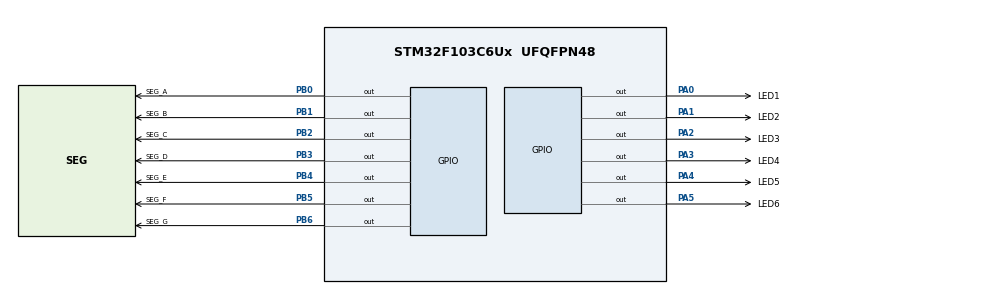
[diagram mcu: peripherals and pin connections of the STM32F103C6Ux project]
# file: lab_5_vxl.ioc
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Mcu.Family=STM32F1
Mcu.Name=STM32F103C6Ux
Mcu.Package=UFQFPN48
NVIC.PriorityGroup=NVIC_PRIORITYGROUP_4
PA0-WKUP.GPIO_Label=LED1
PA0-WKUP.Signal=GPIO_Output
PA1.GPIO_Label=LED2
PA1.Signal=GPIO_Output
PA2.GPIO_Label=LED3
PA2.Signal=GPIO_Output
PA3.GPIO_Label=LED4
PA3.Signal=GPIO_Output
PA4.GPIO_Label=LED5
PA4.Signal=GPIO_Output
PA5.GPIO_Label=LED6
PA5.Signal=GPIO_Output
PB0.GPIO_Label=SEG_A
PB0.Signal=GPIO_Output
PB1.GPIO_Label=SEG_B
PB1.Signal=GPIO_Output
PB2.GPIO_Label=SEG_C
PB2.Signal=GPIO_Output
PB3.GPIO_Label=SEG_D
PB3.Signal=GPIO_Output
PB4.GPIO_Label=SEG_E
PB4.Signal=GPIO_Output
PB5.GPIO_Label=SEG_F
PB5.Signal=GPIO_Output
PB6.GPIO_Label=SEG_G
PB6.Signal=GPIO_Output
ProjectManager.HeapSize=0x200
ProjectManager.StackSize=0x400
ProjectManager.TargetToolchain=STM32CubeIDE
RCC.APB1Freq_Value=8000000
RCC.APB2Freq_Value=8000000
VP_SYS_VS_ND.Mode=No_Debug
board=custom

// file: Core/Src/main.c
/* USER CODE BEGIN Header */
/**
  ******************************************************************************
  * @file           : main.c
  * @brief          : Main program body
  ******************************************************************************
  */

/* USER CODE END Header */

#include "main.h"

/* USER CODE BEGIN PD */

#define SCAN_COUNT      250
#define SCAN_DELAY_MS   2

/* Mau den */
#define RED      0
#define YELLOW   1
#define GREEN    2

/* USER CODE END PD */

void SystemClock_Config(void);
static void MX_GPIO_Init(void);

/* USER CODE BEGIN PFP */

void display7SEG(int num, uint32_t GPIO_Pin);

void allLEDOff(void);

void showTraffic(
    uint8_t verticalColor,
    uint8_t horizontalColor,
    GPIO_PinState phase
);

void runTrafficSecond(
    int verticalDisplay,
    int horizontalDisplay,
    uint8_t verticalColor,
    uint8_t horizontalColor
);

/* USER CODE END PFP */

/* USER CODE BEGIN 0 */

void display7SEG(int num, uint32_t GPIO_Pin)
{
    char segNumber[10] =
    {
        0xC0,
        0xF9,
        0xA4,
        0xB0,
        0x99,
        0x92,
        0x82,
        0xF8,
        0x80,
        0x90
    };

    for (int i = 0; i < 7; ++i)
    {
        HAL_GPIO_WritePin(
            GPIOB,
            GPIO_Pin << i,
            (segNumber[num] >> i) & 1
        );
    }
}

void allLEDOff(void)
{
    HAL_GPIO_WritePin(
        GPIOA,
        GPIO_PIN_1 |
        GPIO_PIN_2 |
        GPIO_PIN_3 |
        GPIO_PIN_4 |
        GPIO_PIN_5 |
        GPIO_PIN_6,
        GPIO_PIN_SET
    );
}

void showTraffic(
    uint8_t verticalColor,
    uint8_t horizontalColor,
    GPIO_PinState phase
)
{
    HAL_GPIO_WritePin(
        GPIOA,
        GPIO_PIN_1 |
        GPIO_PIN_2 |
        GPIO_PIN_3 |
        GPIO_PIN_4 |
        GPIO_PIN_5 |
        GPIO_PIN_6,
        GPIO_PIN_SET
    );

    if (horizontalColor == RED)
    {
        HAL_GPIO_WritePin(
            GPIOA,
            GPIO_PIN_1,
            phase
        );
    }

    else if (horizontalColor == YELLOW)
    {
        HAL_GPIO_WritePin(
            GPIOA,
            GPIO_PIN_2,
            phase
        );
    }

    else if (horizontalColor == GREEN)
    {
        HAL_GPIO_WritePin(
            GPIOA,
            GPIO_PIN_3,
            phase
        );
    }

    if (verticalColor == RED)
    {
        HAL_GPIO_WritePin(
            GPIOA,
            GPIO_PIN_4,
            phase
        );
    }

    else if (verticalColor == YELLOW)
    {
        HAL_GPIO_WritePin(
            GPIOA,
            GPIO_PIN_5,
            phase
        );
    }

    else if (verticalColor == GREEN)
    {
        HAL_GPIO_WritePin(
            GPIOA,
            GPIO_PIN_6,
            phase
        );
    }
}

void runTrafficSecond(
    int verticalDisplay,
    int horizontalDisplay,
    uint8_t verticalColor,
    uint8_t horizontalColor
)
{
    for (int i = 0; i < SCAN_COUNT; i++)
    {
        /*
         * ====================================================
         * PHA 1
         * ====================================================
         */
        showTraffic(
            verticalColor,
            horizontalColor,
            GPIO_PIN_RESET
        );

        display7SEG(
            verticalDisplay,
            GPIO_PIN_0
        );

        display7SEG(
            horizontalDisplay,
            GPIO_PIN_7
        );

        HAL_Delay(SCAN_DELAY_MS);

        /*
         * ====================================================
         * PHA 2
         * ====================================================
         */
        showTraffic(
            verticalColor,
            horizontalColor,
            GPIO_PIN_SET
        );

        display7SEG(
            verticalDisplay,
            GPIO_PIN_0
        );

        display7SEG(
            horizontalDisplay,
            GPIO_PIN_7
        );

        HAL_Delay(SCAN_DELAY_MS);
    }
}

/* USER CODE END 0 */

int main(void)
{

    /* MCU Configuration--------------------------------------------------------*/

    HAL_Init();

    /* Configure the system clock */
    SystemClock_Config();

    /* Initialize all configured peripherals */
    MX_GPIO_Init();

    /* USER CODE BEGIN 2 */

    allLEDOff();

    /* USER CODE END 2 */

    /* Infinite loop */
    while (1)
    {

        runTrafficSecond(
            5,
            3,
            RED,
            GREEN
        );

        runTrafficSecond(
            4,
            2,
            RED,
            GREEN
        );

        runTrafficSecond(
            3,
            1,
            RED,
            GREEN
        );

        runTrafficSecond(
            2,
            2,
            RED,
            YELLOW
        );

        runTrafficSecond(
            1,
            1,
            RED,
            YELLOW
        );

        runTrafficSecond(
            3,
            5,
            GREEN,
            RED
        );

        runTrafficSecond(
            2,
            4,
            GREEN,
            RED
        );

        runTrafficSecond(
            1,
            3,
            GREEN,
            RED
        );

        runTrafficSecond(
            2,
            2,
            YELLOW,
            RED
        );

        runTrafficSecond(
            1,
            1,
            YELLOW,
            RED
        );

        /*
         * ====================================================
         * QUAY LAI GIAI DOAN 1
         * ====================================================
         */
    }

}

void SystemClock_Config(void)
{
    RCC_OscInitTypeDef RCC_OscInitStruct = {0};
    RCC_ClkInitTypeDef RCC_ClkInitStruct = {0};

    /*
     * HSI Clock
     */
    RCC_OscInitStruct.OscillatorType =
        RCC_OSCILLATORTYPE_HSI;

    RCC_OscInitStruct.HSIState =
        RCC_HSI_ON;

    RCC_OscInitStruct.HSICalibrationValue =
        RCC_HSICALIBRATION_DEFAULT;

    RCC_OscInitStruct.PLL.PLLState =
        RCC_PLL_NONE;

    if (HAL_RCC_OscConfig(&RCC_OscInitStruct) != HAL_OK)
    {
        Error_Handler();
    }

    /*
     * CPU / AHB / APB Clock
     */
    RCC_ClkInitStruct.ClockType =
        RCC_CLOCKTYPE_HCLK |
        RCC_CLOCKTYPE_SYSCLK |
        RCC_CLOCKTYPE_PCLK1 |
        RCC_CLOCKTYPE_PCLK2;

    RCC_ClkInitStruct.SYSCLKSource =
        RCC_SYSCLKSOURCE_HSI;

    RCC_ClkInitStruct.AHBCLKDivider =
        RCC_SYSCLK_DIV1;

    RCC_ClkInitStruct.APB1CLKDivider =
        RCC_HCLK_DIV1;

    RCC_ClkInitStruct.APB2CLKDivider =
        RCC_HCLK_DIV1;

    if (HAL_RCC_ClockConfig(
            &RCC_ClkInitStruct,
            FLASH_LATENCY_0) != HAL_OK)
    {
        Error_Handler();
    }
}

static void MX_GPIO_Init(void)
{
    GPIO_InitTypeDef GPIO_InitStruct = {0};

    /*
     * ========================================================
     * GPIO CLOCK
     * ========================================================
     */
    __HAL_RCC_GPIOA_CLK_ENABLE();
    __HAL_RCC_GPIOB_CLK_ENABLE();

    HAL_GPIO_WritePin(
        GPIOA,
        GPIO_PIN_1 |
        GPIO_PIN_2 |
        GPIO_PIN_3 |
        GPIO_PIN_4 |
        GPIO_PIN_5 |
        GPIO_PIN_6,
        GPIO_PIN_SET
    );

    GPIO_InitStruct.Pin =
        GPIO_PIN_1 |
        GPIO_PIN_2 |
        GPIO_PIN_3 |
        GPIO_PIN_4 |
        GPIO_PIN_5 |
        GPIO_PIN_6;

    GPIO_InitStruct.Mode =
        GPIO_MODE_OUTPUT_PP;

    GPIO_InitStruct.Pull =
        GPIO_NOPULL;

    GPIO_InitStruct.Speed =
        GPIO_SPEED_FREQ_LOW;

    HAL_GPIO_Init(
        GPIOA,
        &GPIO_InitStruct
    );

    /*
     * ========================================================
     * GPIOB
     *
     * PB0 -> PB13
     * Cho 2 7SEG
     * ========================================================
     */

    HAL_GPIO_WritePin(
        GPIOB,
        GPIO_PIN_0 |
        GPIO_PIN_1 |
        GPIO_PIN_2 |
        GPIO_PIN_3 |
        GPIO_PIN_4 |
        GPIO_PIN_5 |
        GPIO_PIN_6 |
        GPIO_PIN_7 |
        GPIO_PIN_8 |
        GPIO_PIN_9 |
        GPIO_PIN_10 |
        GPIO_PIN_11 |
        GPIO_PIN_12 |
        GPIO_PIN_13,
        GPIO_PIN_RESET
    );

    GPIO_InitStruct.Pin =
        GPIO_PIN_0 |
        GPIO_PIN_1 |
        GPIO_PIN_2 |
        GPIO_PIN_3 |
        GPIO_PIN_4 |
        GPIO_PIN_5 |
        GPIO_PIN_6 |
        GPIO_PIN_7 |
        GPIO_PIN_8 |
        GPIO_PIN_9 |
        GPIO_PIN_10 |
        GPIO_PIN_11 |
        GPIO_PIN_12 |
        GPIO_PIN_13;

    GPIO_InitStruct.Mode =
        GPIO_MODE_OUTPUT_PP;

    GPIO_InitStruct.Pull =
        GPIO_NOPULL;

    GPIO_InitStruct.Speed =
        GPIO_SPEED_FREQ_LOW;

    HAL_GPIO_Init(
        GPIOB,
        &GPIO_InitStruct
    );
}

void Error_Handler(void)
{
    __disable_irq();

    while (1)
    {
    }
}
